VERSION 5.8 ;
BUSBITCHARS "[]" ;
DIVIDERCHAR "/" ;
UNITS
    DATABASE MICRONS 1000 ;
END UNITS

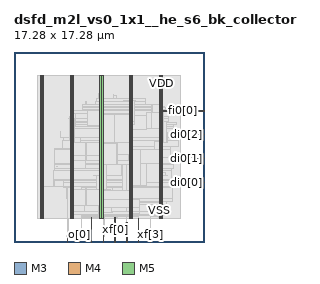
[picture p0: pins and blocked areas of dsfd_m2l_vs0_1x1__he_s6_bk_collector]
MACRO dsfd_m2l_vs0_1x1__he_s6_bk_collector
  FOREIGN dsfd_m2l_vs0_1x1__he_s6_bk_collector 0 0 ;
  CLASS BLOCK ;
  SIZE 17.28 BY 17.28 ;
  PIN ck[0]
    DIRECTION INPUT ;
    USE SIGNAL ;
    PORT
      LAYER M3 ;
        RECT  4.86 0 4.878 0.144 ;
    END
    PORT
      LAYER M3 ;
        RECT  4.86 0.108 4.878 0.52 ;
    END
  END ck[0]
  PIN di0[0]
    DIRECTION INPUT ;
    USE SIGNAL ;
    PORT
      LAYER M4 ;
        RECT  17.088 5.424 17.28 5.448 ;
    END
    PORT
      LAYER M4 ;
        RECT  16.513 5.424 17.1 5.448 ;
    END
  END di0[0]
  PIN di0[1]
    DIRECTION INPUT ;
    USE SIGNAL ;
    PORT
      LAYER M4 ;
        RECT  17.088 7.584 17.28 7.608 ;
    END
    PORT
      LAYER M4 ;
        RECT  16.513 7.584 17.1 7.608 ;
    END
  END di0[1]
  PIN di0[2]
    DIRECTION INPUT ;
    USE SIGNAL ;
    PORT
      LAYER M4 ;
        RECT  17.088 9.744 17.28 9.768 ;
    END
    PORT
      LAYER M4 ;
        RECT  16.513 9.744 17.1 9.768 ;
    END
  END di0[2]
  PIN fi0[0]
    DIRECTION INPUT ;
    USE SIGNAL ;
    PORT
      LAYER M4 ;
        RECT  17.088 11.904 17.28 11.928 ;
    END
    PORT
      LAYER M4 ;
        RECT  13.637 11.904 17.1 11.928 ;
    END
  END fi0[0]
  PIN o[0]
    DIRECTION OUTPUT ;
    USE SIGNAL ;
    PORT
      LAYER M5 ;
        RECT  5.952 0 5.976 0.192 ;
    END
    PORT
      LAYER M5 ;
        RECT  5.952 0.144 5.976 0.227 ;
    END
  END o[0]
  PIN o[1]
    DIRECTION OUTPUT ;
    USE SIGNAL ;
    PORT
      LAYER M3 ;
        RECT  7.02 0 7.038 0.144 ;
    END
    PORT
      LAYER M3 ;
        RECT  7.02 0.108 7.038 2.191 ;
    END
  END o[1]
  PIN rs[0]
    DIRECTION INPUT ;
    USE SIGNAL ;
    PORT
      LAYER M5 ;
        RECT  8.112 0 8.136 0.192 ;
    END
    PORT
      LAYER M5 ;
        RECT  8.112 0.144 8.136 0.563 ;
    END
  END rs[0]
  PIN xf[0]
    DIRECTION INPUT ;
    USE SIGNAL ;
    PORT
      LAYER M3 ;
        RECT  9.18 0 9.198 0.144 ;
    END
    PORT
      LAYER M3 ;
        RECT  9.18 0.108 9.198 2.191 ;
    END
  END xf[0]
  PIN xf[1]
    DIRECTION INPUT ;
    USE SIGNAL ;
    PORT
      LAYER M5 ;
        RECT  10.272 0 10.296 0.192 ;
    END
    PORT
      LAYER M5 ;
        RECT  10.272 0.144 10.296 1.763 ;
    END
  END xf[1]
  PIN xf[2]
    DIRECTION INPUT ;
    USE SIGNAL ;
    PORT
      LAYER M3 ;
        RECT  11.34 0 11.358 0.144 ;
    END
    PORT
      LAYER M3 ;
        RECT  11.34 0.108 11.358 2.101 ;
    END
  END xf[2]
  PIN xf[3]
    DIRECTION INPUT ;
    USE SIGNAL ;
    PORT
      LAYER M5 ;
        RECT  12.384 0 12.408 0.192 ;
    END
    PORT
      LAYER M5 ;
        RECT  12.384 0.144 12.408 0.227 ;
    END
  END xf[3]
  PIN VDD
    DIRECTION INOUT ;
    USE POWER ;
    PORT
      LAYER M5 ;
        RECT  13.392 2.151 13.512 15.129 ;
        RECT  10.692 2.151 10.812 15.129 ;
        RECT  7.992 2.151 8.112 15.129 ;
        RECT  5.292 2.151 5.412 15.129 ;
        RECT  2.592 2.151 2.712 15.129 ;
    END
  END VDD
  PIN VSS
    DIRECTION INOUT ;
    USE GROUND ;
    PORT
      LAYER M5 ;
        RECT  13.2 2.137 13.32 15.143 ;
        RECT  10.5 2.137 10.62 15.143 ;
        RECT  7.8 2.137 7.92 15.143 ;
        RECT  5.1 2.137 5.22 15.143 ;
        RECT  2.4 2.137 2.52 15.143 ;
    END
  END VSS
  # OT_OBS_CLOSED layer=M5 d_um=1.536 added=13
  OBS
    LAYER RVTN ;
     RECT  2.16 2.16 15.12 2.295 ;
     RECT  2.16 2.565 15.12 2.835 ;
     RECT  2.16 3.105 15.12 3.375 ;
     RECT  2.16 3.645 15.12 3.915 ;
     RECT  2.16 4.185 15.12 4.455 ;
     RECT  2.16 4.725 15.12 4.995 ;
     RECT  2.16 5.265 15.12 5.535 ;
     RECT  2.16 5.805 15.12 6.075 ;
     RECT  2.16 6.345 15.12 6.615 ;
     RECT  2.16 6.885 15.12 7.155 ;
     RECT  2.16 7.425 15.12 7.695 ;
     RECT  2.16 7.965 15.12 8.235 ;
     RECT  2.16 8.505 15.12 8.775 ;
     RECT  2.16 9.045 15.12 9.315 ;
     RECT  2.16 9.585 15.12 9.855 ;
     RECT  2.16 10.125 15.12 10.395 ;
     RECT  2.16 10.665 15.12 10.935 ;
     RECT  2.16 11.205 15.12 11.475 ;
     RECT  2.16 11.745 15.12 12.015 ;
     RECT  2.16 12.285 15.12 12.555 ;
     RECT  2.16 12.825 15.12 13.095 ;
     RECT  2.16 13.365 15.12 13.635 ;
     RECT  2.16 13.905 15.12 14.175 ;
     RECT  2.16 14.445 15.12 14.715 ;
     RECT  2.16 14.985 15.12 15.12 ;
    LAYER RVTP ;
     RECT  2.16 2.295 15.12 2.565 ;
     RECT  2.16 2.835 15.12 3.105 ;
     RECT  2.16 3.375 15.12 3.645 ;
     RECT  2.16 3.915 15.12 4.185 ;
     RECT  2.16 4.455 15.12 4.725 ;
     RECT  2.16 4.995 15.12 5.265 ;
     RECT  2.16 5.535 15.12 5.805 ;
     RECT  2.16 6.075 15.12 6.345 ;
     RECT  2.16 6.615 15.12 6.885 ;
     RECT  2.16 7.155 15.12 7.425 ;
     RECT  2.16 7.695 15.12 7.965 ;
     RECT  2.16 8.235 15.12 8.505 ;
     RECT  2.16 8.775 15.12 9.045 ;
     RECT  2.16 9.315 15.12 9.585 ;
     RECT  2.16 9.855 15.12 10.125 ;
     RECT  2.16 10.395 15.12 10.665 ;
     RECT  2.16 10.935 15.12 11.205 ;
     RECT  2.16 11.475 15.12 11.745 ;
     RECT  2.16 12.015 15.12 12.285 ;
     RECT  2.16 12.555 15.12 12.825 ;
     RECT  2.16 13.095 15.12 13.365 ;
     RECT  2.16 13.635 15.12 13.905 ;
     RECT  2.16 14.175 15.12 14.445 ;
     RECT  2.16 14.715 15.12 14.985 ;
    LAYER M1 ;
     RECT  2.16 2.151 15.12 15.129 ;
    LAYER M2 ;
     RECT  4.783 0.531 4.883 0.549 ;
     RECT  2.16 2.151 10.471 15.129 ;
     RECT  10.471 2.106 10.715 15.129 ;
     RECT  10.715 2.151 15.12 15.129 ;
     RECT  15.12 5.58 16.547 5.598 ;
     RECT  15.12 7.704 16.547 7.722 ;
     RECT  15.12 9.9 16.547 9.918 ;
    LAYER M3 ;
     RECT  4.788 0.52 4.878 0.554 ;
     RECT  4.788 0.554 4.806 0.557 ;
     RECT  10.188 1.723 10.206 2.101 ;
     RECT  8.172 0.523 8.19 2.143 ;
     RECT  6.156 0.187 6.174 2.191 ;
     RECT  7.815 2.143 8.19 2.191 ;
     RECT  13.215 2.143 13.305 2.191 ;
     RECT  13.215 2.191 13.446 2.227 ;
     RECT  12.384 0.187 12.402 2.299 ;
     RECT  13.176 2.227 13.446 2.299 ;
     RECT  5.115 2.143 5.205 2.335 ;
     RECT  6.156 2.191 8.19 2.335 ;
     RECT  9.18 2.191 9.45 2.335 ;
     RECT  10.188 2.101 11.358 2.335 ;
     RECT  6.156 2.335 11.358 2.371 ;
     RECT  12.384 2.299 13.446 2.371 ;
     RECT  2.415 2.143 2.505 2.413 ;
     RECT  5.115 2.335 5.238 2.413 ;
     RECT  6.156 2.371 14.022 2.489 ;
     RECT  5.115 2.413 5.397 2.497 ;
     RECT  6.156 2.489 13.554 2.497 ;
     RECT  5.115 2.497 13.554 2.795 ;
     RECT  6.408 2.795 13.554 3.451 ;
     RECT  5.115 2.795 5.397 3.685 ;
     RECT  5.076 3.685 5.562 3.721 ;
     RECT  6.408 3.451 13.842 3.721 ;
     RECT  5.04 3.721 14.418 3.931 ;
     RECT  4.752 3.931 14.418 4.999 ;
     RECT  3.492 5.029 3.51 5.069 ;
     RECT  4.5 4.999 14.418 5.071 ;
     RECT  4.464 5.071 14.418 5.431 ;
     RECT  16.524 5.419 16.542 5.603 ;
     RECT  3.636 5.071 3.654 5.611 ;
     RECT  4.464 5.431 14.562 5.611 ;
     RECT  3.636 5.611 14.742 5.729 ;
     RECT  3.636 5.729 14.31 6.539 ;
     RECT  3.708 6.539 14.31 6.691 ;
     RECT  3.708 6.691 14.49 7.079 ;
     RECT  3.708 7.079 14.346 7.115 ;
     RECT  16.524 7.579 16.542 7.727 ;
     RECT  3.708 7.115 14.238 8.429 ;
     RECT  3.708 8.429 3.726 8.525 ;
     RECT  4.572 8.429 14.238 8.671 ;
     RECT  4.572 8.671 14.922 9.211 ;
     RECT  4.464 9.211 14.922 9.239 ;
     RECT  4.464 9.239 14.85 9.275 ;
     RECT  4.464 9.275 14.49 9.481 ;
     RECT  4.248 9.481 14.49 9.509 ;
     RECT  16.524 9.739 16.542 9.923 ;
     RECT  4.248 9.509 4.266 10.085 ;
     RECT  5.004 9.509 14.49 10.319 ;
     RECT  5.04 10.319 14.49 10.471 ;
     RECT  5.04 10.471 14.526 10.705 ;
     RECT  5.04 10.705 14.814 10.859 ;
     RECT  5.04 10.859 14.058 10.931 ;
     RECT  5.04 10.931 14.022 11.227 ;
     RECT  5.004 11.227 14.022 11.435 ;
     RECT  5.115 11.435 14.022 11.975 ;
     RECT  6.264 11.975 14.022 12.047 ;
     RECT  6.264 12.047 13.806 12.209 ;
     RECT  6.264 12.209 13.698 12.281 ;
     RECT  6.264 12.281 13.497 12.479 ;
     RECT  7.416 12.479 13.497 12.515 ;
     RECT  6.48 12.479 6.57 12.749 ;
     RECT  6.48 12.749 6.498 12.785 ;
     RECT  7.416 12.515 11.97 12.821 ;
     RECT  7.488 12.821 11.97 13.019 ;
     RECT  7.488 13.019 8.097 13.055 ;
     RECT  9.036 13.019 9.306 13.325 ;
     RECT  9.036 13.325 9.054 13.397 ;
     RECT  7.704 13.055 8.097 13.469 ;
     RECT  2.415 2.413 2.697 14.867 ;
     RECT  5.115 11.975 5.397 14.867 ;
     RECT  7.815 13.469 8.097 14.867 ;
     RECT  10.515 13.019 10.797 14.867 ;
     RECT  13.215 12.515 13.497 14.867 ;
     RECT  2.415 14.867 2.505 15.137 ;
     RECT  5.115 14.867 5.205 15.137 ;
     RECT  7.815 14.867 7.905 15.137 ;
     RECT  10.515 14.867 10.605 15.137 ;
     RECT  13.215 14.867 13.305 15.137 ;
    LAYER M4 ;
     RECT  2.408 2.148 2.512 15.132 ;
     RECT  2.512 2.418 2.704 14.862 ;
     RECT  3.841 6.864 3.953 6.888 ;
     RECT  3.697 8.496 4.405 8.52 ;
     RECT  2.704 5.04 4.885 5.064 ;
     RECT  4.777 0.528 4.931 0.552 ;
     RECT  4.405 8.496 5.065 9.24 ;
     RECT  4.741 3.936 5.108 3.96 ;
     RECT  4.885 4.944 5.108 5.064 ;
     RECT  5.065 8.496 5.108 9.528 ;
     RECT  4.993 11.232 5.108 11.256 ;
     RECT  5.108 2.148 5.212 15.132 ;
     RECT  5.212 2.418 5.404 14.862 ;
     RECT  5.404 10.512 5.581 11.688 ;
     RECT  5.404 8.976 6.041 9.528 ;
     RECT  5.404 3.696 6.113 5.064 ;
     RECT  5.941 0.192 6.185 0.216 ;
     RECT  5.404 6.672 6.476 7.368 ;
     RECT  6.113 3.696 6.517 4.968 ;
     RECT  6.476 6.672 6.545 7.944 ;
     RECT  6.545 7.392 6.563 7.944 ;
     RECT  6.517 3.36 6.581 4.968 ;
     RECT  6.581 3.36 6.604 3.576 ;
     RECT  5.581 11.232 6.685 11.688 ;
     RECT  6.581 4.656 7.477 4.968 ;
     RECT  7.225 6.048 7.477 6.072 ;
     RECT  6.649 2.304 7.729 2.328 ;
     RECT  6.604 3.408 7.729 3.576 ;
     RECT  6.563 7.392 7.765 7.416 ;
     RECT  7.729 2.304 7.808 3.576 ;
     RECT  7.477 4.656 7.808 6.072 ;
     RECT  7.765 7.392 7.808 7.656 ;
     RECT  6.041 8.976 7.808 9 ;
     RECT  6.685 10.608 7.808 11.976 ;
     RECT  7.808 2.148 7.912 15.132 ;
     RECT  7.912 2.418 8.104 14.862 ;
     RECT  8.101 0.528 8.201 0.552 ;
     RECT  8.104 2.688 8.453 7.944 ;
     RECT  8.453 2.688 8.915 4.92 ;
     RECT  8.104 11.424 9.011 11.64 ;
     RECT  8.104 8.976 9.109 9.96 ;
     RECT  9.011 11.424 9.109 11.544 ;
     RECT  9.109 8.976 9.281 11.544 ;
     RECT  9.281 8.976 9.395 9.72 ;
     RECT  8.453 6.048 9.745 7.944 ;
     RECT  8.915 2.832 9.889 4.92 ;
     RECT  9.745 6.048 9.889 7.992 ;
     RECT  9.889 2.832 10.213 7.992 ;
     RECT  10.177 1.728 10.307 1.752 ;
     RECT  10.213 2.784 10.508 7.992 ;
     RECT  9.395 9.456 10.508 9.72 ;
     RECT  9.281 10.896 10.508 11.544 ;
     RECT  9.925 12.864 10.508 12.888 ;
     RECT  10.508 2.148 10.612 15.132 ;
     RECT  10.612 2.418 10.804 14.862 ;
     RECT  10.804 12.864 11.045 12.888 ;
     RECT  10.804 2.592 11.411 3.816 ;
     RECT  10.804 5.184 11.549 8.424 ;
     RECT  10.804 10.272 12.013 11.544 ;
     RECT  11.549 5.184 12.017 7.128 ;
     RECT  12.013 10.272 12.089 11.784 ;
     RECT  12.373 0.192 12.457 0.216 ;
     RECT  12.089 10.32 12.524 11.784 ;
     RECT  11.549 8.4 12.733 8.424 ;
     RECT  11.411 3.552 13.208 3.576 ;
     RECT  12.017 5.424 13.208 7.128 ;
     RECT  12.733 8.4 13.208 9.096 ;
     RECT  12.524 10.32 13.208 12.504 ;
     RECT  13.208 2.148 13.312 15.132 ;
     RECT  13.312 2.418 13.504 14.862 ;
     RECT  13.504 9.072 13.637 11.928 ;
     RECT  13.504 6.048 13.781 6.312 ;
     RECT  13.637 9.072 13.889 10.92 ;
     RECT  13.889 9.072 13.925 9.96 ;
     RECT  13.781 6.048 13.961 6.072 ;
     RECT  13.925 9.936 13.961 9.96 ;
     RECT  13.504 7.68 13.997 7.704 ;
    LAYER M5 ;
     RECT  4.896 0.517 4.92 2.137 ;
     RECT  2.4 2.137 2.52 2.151 ;
     RECT  4.896 2.137 5.22 2.151 ;
     RECT  7.8 2.137 7.92 2.151 ;
     RECT  10.5 2.137 10.62 2.151 ;
     RECT  13.2 2.137 13.32 2.151 ;
     RECT  10.5 2.151 10.812 2.581 ;
     RECT  7.8 2.151 8.112 2.677 ;
     RECT  10.5 2.581 11.4 2.773 ;
     RECT  7.8 2.677 8.904 3.109 ;
     RECT  10.224 2.773 11.4 3.109 ;
     RECT  7.8 3.109 11.4 3.827 ;
     RECT  7.8 3.827 10.812 4.643 ;
     RECT  6.528 3.349 6.552 4.787 ;
     RECT  7.8 4.643 8.808 4.787 ;
     RECT  4.896 2.151 5.412 4.979 ;
     RECT  10.5 4.643 10.812 7.381 ;
     RECT  10.368 7.381 10.812 8.003 ;
     RECT  5.1 4.979 5.412 8.485 ;
     RECT  9.36 7.093 9.384 8.965 ;
     RECT  6.528 7.909 6.552 9.011 ;
     RECT  9.12 8.965 9.384 9.011 ;
     RECT  7.8 4.787 8.112 9.061 ;
     RECT  9.12 9.011 9.144 9.061 ;
     RECT  4.416 8.485 5.412 9.251 ;
     RECT  5.1 9.251 5.412 10.501 ;
     RECT  10.5 8.003 10.812 10.645 ;
     RECT  10.5 10.645 10.968 10.931 ;
     RECT  5.1 10.501 5.544 11.267 ;
     RECT  7.8 9.061 9.144 11.555 ;
     RECT  7.8 11.555 9 11.651 ;
     RECT  13.2 2.151 13.512 11.749 ;
     RECT  12.576 11.749 13.512 12.515 ;
     RECT  10.5 10.931 10.92 12.899 ;
     RECT  2.4 2.151 2.712 15.129 ;
     RECT  5.1 11.267 5.412 15.129 ;
     RECT  7.8 11.651 8.112 15.129 ;
     RECT  10.5 12.899 10.812 15.129 ;
     RECT  13.2 12.515 13.512 15.129 ;
     RECT  2.4 15.129 2.52 15.143 ;
     RECT  5.1 15.129 5.22 15.143 ;
     RECT  7.8 15.129 7.92 15.143 ;
     RECT  10.5 15.129 10.62 15.143 ;
     RECT  13.2 15.129 13.32 15.143 ;
     RECT  8.904 2.773 10.224 3.109 ;
     RECT  5.412 3.349 6.528 4.787 ;
     RECT  6.552 3.349 7.8 4.787 ;
     RECT  8.112 7.093 9.36 8.965 ;
     RECT  9.384 7.093 10.5 7.381 ;
     RECT  9.384 7.381 10.368 8.003 ;
     RECT  5.412 7.909 6.528 9.011 ;
     RECT  6.552 7.909 7.8 9.011 ;
     RECT  9.384 8.003 10.5 9.011 ;
     RECT  8.112 8.965 9.12 9.061 ;
     RECT  5.412 9.011 5.544 10.501 ;
     RECT  9.144 9.011 10.5 11.555 ;
     RECT  9 11.555 10.5 11.651 ;
  END
END dsfd_m2l_vs0_1x1__he_s6_bk_collector
END LIBRARY
